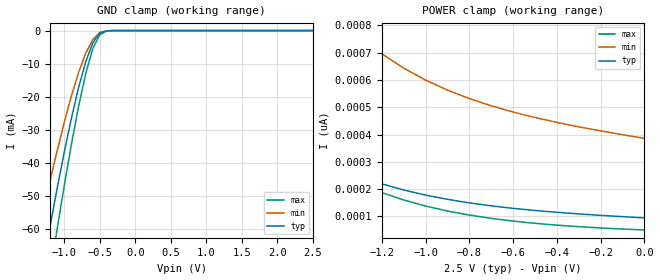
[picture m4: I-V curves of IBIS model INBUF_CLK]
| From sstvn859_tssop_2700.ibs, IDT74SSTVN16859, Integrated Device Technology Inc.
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|   Model INBUF_CLK
[Model]   INBUF_CLK
Model_type   Input
Polarity   Non-Inverting
Vinl =  0.79000V
Vinh =  1.71000V
C_comp   3.28000pF   3.28000pF   3.28000pF
[Temperature Range]   25.00000   70.00000   0.000
[Voltage Range]   2.50000V   2.30000V   2.70000V
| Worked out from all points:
|   GND clamp passes 1 mA (typ) near -0.51 V on its own axis
[GND_clamp]
| voltage   I(typ)   I(min)   I(max)
-2.5V     -221.5mA   -180.4mA   -257.4mA
-1.4V     -82.75mA   -64.31mA   -101.1mA
-1.3V     -70.61mA   -54.52mA   -86.97mA
-1.2V     -58.76mA   -45.05mA   -73.07mA
-1.1V     -47.31mA   -35.99mA   -59.51mA
-900mV    -26.27mA   -19.6mA    -34.1mA
-800mV    -17.12mA   -12.63mA   -22.79mA
-700mV    -9.383mA   -6.816mA   -12.96mA
-600mV    -3.667mA   -2.639mA   -5.378mA
-500mV    -745.8uA   -564.9uA   -1.16mA
-300mV    -3.071uA   -4.017uA   -3.937uA
2.5V      94.51pA    413.5pA    44.36pA
[POWER_clamp]
| voltage   I(typ)   I(min)   I(max)
-2.5V     1.398nA    3.51nA     1.623nA
-2.2V     889.8pA    2.286nA    1.003nA
-2.1V     764.4pA    1.985nA    850.6pA
-2V       656.9pA    1.728nA    719.6pA
-1.9V     565.1pA    1.509nA    607.8pA
-1.7V     420.9pA    1.168nA    432.1pA
-1.4V     279.1pA    835.6pA    259.6pA
-1.3V     246.4pA    759.4pA    219.9pA
-1.2V     219.2pA    696.1pA    187.1pA
-1V       177.9pA    599.6pA    137.8pA
-700mV    138.6pA    505.4pA    92.57pA
0V        94.51pA    386.3pA    50.07pA
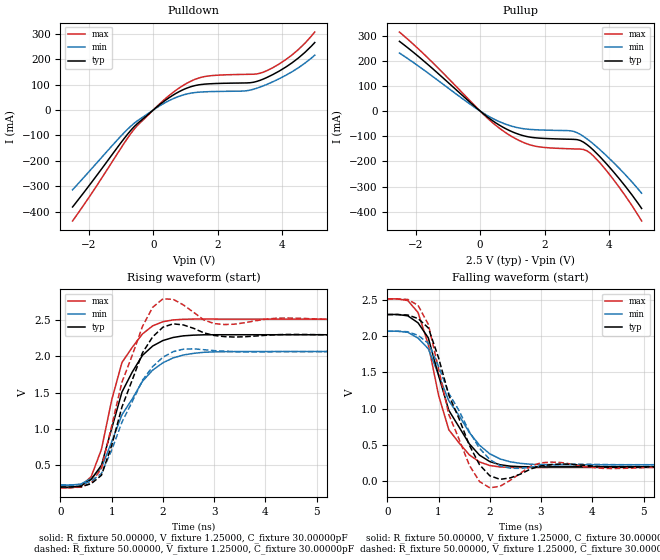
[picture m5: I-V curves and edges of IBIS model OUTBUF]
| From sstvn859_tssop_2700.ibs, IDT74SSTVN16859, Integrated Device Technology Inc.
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|   Model OUTBUF
[Model]   OUTBUF
Model_type   Output
Polarity   Inverting
Vmeas =  1.25000V
Cref = 30.00000pF
Rref =  50.00000
Vref =  1.25000V
C_comp   3.50000pF   3.50000pF   3.50000pF
[Temperature Range]   25.00000   70.00000   0.000
[Voltage Range]   2.50000V   2.30000V   2.70000V
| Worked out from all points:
|   slope of the pulldown table from 0 to 0.375 V, typ, clamps not added: 9.8 ohm
|   slope of the pullup table from 0 to 0.375 V, typ, clamps not added: 10.1 ohm
|   rising waveform, R_fixture 50.00000, V_fixture 1.25000, C_fixture 30.00000pF: 20-80 % time 636ps typ, 784ps min, 562ps max; typ from 0.197 V to 2.3 V
|   rising waveform, R_fixture 50.00000, V_fixture 1.25000, C_fixture 30.00000pF: 20-80 % time 583ps typ, 701ps min, 550ps max; typ from 0.199 V to 2.3 V
|   falling waveform, R_fixture 50.00000, V_fixture 1.25000, C_fixture 30.00000pF: 20-80 % time 673ps typ, 817ps min, 535ps max; typ from 2.3 V to 0.197 V
|   falling waveform, R_fixture 50.00000, V_fixture 1.25000, C_fixture 30.00000pF: 20-80 % time 618ps typ, 749ps min, 518ps max; typ from 2.3 V to 0.199 V
[Pulldown]
| voltage   I(typ)   I(min)   I(max)
-2.5V     -382.1mA   -314.5mA   -437.4mA
-1.1V     -145.6mA   -116.1mA   -169.6mA
-600mV    -66.63mA   -53.03mA   -76.8mA
100mV     10.92mA    8.522mA    12.56mA
600mV     57.64mA    43.69mA    68.13mA
1.1V      89.1mA     64.83mA    109.6mA
1.5V      100.7mA    71.03mA    129.3mA
2.9V      106.7mA    76.05mA    140.5mA
3.2V      112.5mA    85.58mA    142mA
3.5V      127.1mA    99.91mA    154mA
4.3V      186.2mA    151mA      217.4mA
5V        265.8mA    216.1mA    307.2mA
[Pullup]
| voltage   I(typ)   I(min)   I(max)
-2.5V     277.1mA    230.6mA    314.1mA
-1.5V     171.8mA    140.4mA    196.3mA
0V        -3.242nA   -2.817nA   -2.207nA
500mV     -48.16mA   -36.41mA   -58.24mA
900mV     -76.91mA   -56.88mA   -94.98mA
1.7V      -106mA     -74mA      -139.3mA
2.8V      -111.9mA   -78.26mA   -149.8mA
3.1V      -116.8mA   -92.51mA   -151mA
3.4V      -142.8mA   -119.5mA   -166.2mA
3.7V      -180mA     -152.3mA   -204.3mA
4.1V      -237mA     -200.8mA   -267.3mA
5V        -386.9mA   -326.4mA   -436.7mA
[Ramp]
| variable   typ   min   max
dV/dt_r   1.24620/0.15909n   1.08300/0.21706n   1.38720/0.12588n
dV/dt_f   1.25244/0.15723n   1.09230/0.21256n   1.38660/0.14172n
R_load = 50.00000
[Rising Waveform]
R_fixture = 50.00000
V_fixture = 1.25000
V_fixture_min = 1.15000
V_fixture_max = 1.35000
C_fixture = 30.00000pF
| time   V(typ)   V(min)   V(max)
0s        197.2mV    224.9mV    188mV
400ps     214.9mV    240.4mV    213.5mV
600ps     303.5mV    317.7mV    342.8mV
800ps     498.8mV    463.8mV    717.9mV
1ns       1.006V     823.8mV    1.398V
1.2ns     1.508V     1.195V     1.915V
1.6ns     2.014V     1.655V     2.309V
2ns       2.219V     1.912V     2.478V
3ns       2.298V     2.062V     2.514V
10ns      2.298V     2.067V     2.513V
[Rising Waveform]
R_fixture = 50.00000
V_fixture = 1.25000
V_fixture_min = 1.15000
V_fixture_max = 1.35000
C_fixture = 30.00000pF
R_dut = 0.10500
L_dut = 3.80000nH
C_dut = 0.22000pF
| time   V(typ)   V(min)   V(max)
0s        199.1mV    226.5mV    190.1mV
600ps     245mV      279.5mV    253.3mV
800ps     361.4mV    387.1mV    456.7mV
1.2ns     1.302V     1.093V     1.644V
1.6ns     2.048V     1.669V     2.412V
2ns       2.402V     1.988V     2.792V
2.4ns     2.433V     2.099V     2.708V
3.2ns     2.272V     2.071V     2.438V
4.4ns     2.302V     2.066V     2.528V
10ns      2.296V     2.066V     2.511V
[Falling Waveform]
R_fixture = 50.00000
V_fixture = 1.25000
V_fixture_min = 1.15000
V_fixture_max = 1.35000
C_fixture = 30.00000pF
| time   V(typ)   V(min)   V(max)
0s        2.298V     2.067V     2.513V
400ps     2.279V     2.051V     2.49V
600ps     2.182V     1.972V     2.324V
800ps     1.975V     1.825V     1.882V
1ns       1.457V     1.465V     1.184V
1.2ns     975.6mV    1.108V     707.7mV
1.6ns     513.5mV    670.2mV    362.2mV
2ns       268.9mV    376.1mV    214.7mV
3ns       196.4mV    227.9mV    187.5mV
10ns      197.2mV    224.9mV    188mV
[Falling Waveform]
R_fixture = 50.00000
V_fixture = 1.25000
V_fixture_min = 1.15000
V_fixture_max = 1.35000
C_fixture = 30.00000pF
R_dut = 0.10500
L_dut = 3.80000nH
C_dut = 0.22000pF
| time   V(typ)   V(min)   V(max)
0s        2.296V     2.066V     2.511V
600ps     2.242V     2.01V      2.424V
800ps     2.113V     1.901V     2.161V
1.2ns     1.186V     1.21V      917.3mV
1.6ns     495.5mV    681.6mV    219.5mV
2ns       73.48mV    297.4mV    -93.3mV
2.4ns     43.67mV    177.4mV    10.94mV
3.2ns     227.6mV    220.2mV    261.7mV
4.4ns     192.3mV    226.8mV    173.2mV
10ns      199.1mV    226.5mV    190.1mV
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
